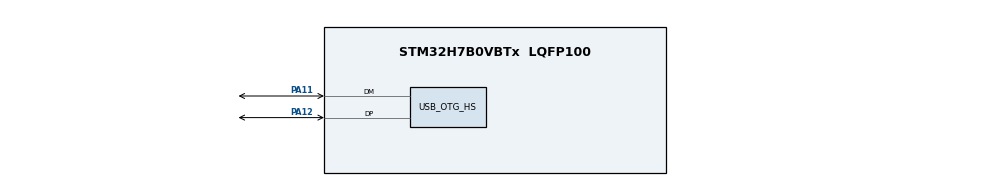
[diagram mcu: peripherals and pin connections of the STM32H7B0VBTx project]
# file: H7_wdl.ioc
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CORTEX_M7.default_mode_Activation=1
Mcu.Family=STM32H7
Mcu.Name=STM32H7B0VBTx
Mcu.Package=LQFP100
NVIC.OTG_HS_IRQn=true\:0\:0\:false\:false\:true\:false\:true\:true
NVIC.PriorityGroup=NVIC_PRIORITYGROUP_4
PA11.Mode=Device_Only_FS
PA11.Signal=USB_OTG_HS_DM
PA12.Mode=Device_Only_FS
PA12.Signal=USB_OTG_HS_DP
PH0-OSC_IN.Mode=HSE-External-Oscillator
PH0-OSC_IN.Signal=RCC_OSC_IN
PH1-OSC_OUT.Mode=HSE-External-Oscillator
PH1-OSC_OUT.Signal=RCC_OSC_OUT
ProjectManager.HeapSize=0x10000
ProjectManager.StackSize=0x10000
ProjectManager.TargetToolchain=STM32CubeIDE
RCC.ADCFreq_Value=280000000
RCC.APB1Freq_Value=140000000
RCC.APB2Freq_Value=140000000
RCC.APB3Freq_Value=140000000
RCC.APB4Freq_Value=140000000
RCC.CDPPRE=RCC_APB3_DIV2
RCC.CDPPRE1=RCC_APB1_DIV2
RCC.CDPPRE2=RCC_APB2_DIV2
RCC.CortexFreq_Value=280000000
RCC.DIVM1=5
RCC.DIVM2=5
RCC.DIVM3=5
RCC.DIVN1=112
RCC.DIVN2=112
RCC.DIVN3=112
RCC.HCLKFreq_Value=280000000
RCC.HSE_VALUE=25000000
RCC.PLL2FRACN=0
RCC.PLL3FRACN=0
RCC.PLLFRACN=0
RCC.PLLSourceVirtual=RCC_PLLSOURCE_HSE
RCC.SRDPPRE=RCC_APB4_DIV2
RCC.SYSCLKFreq_VALUE=280000000
RCC.SYSCLKSource=RCC_SYSCLKSOURCE_PLLCLK
RCC.USBCLockSelection=RCC_USBCLKSOURCE_HSI48
RCC.USBFreq_Value=48000000
USB_DEVICE.CLASS_NAME_HS=CDC
USB_DEVICE.USBD_LPM_ENABLED=0
USB_DEVICE.USBD_MAX_STR_DESC_SIZ=512
USB_DEVICE.VirtualMode=Cdc
USB_DEVICE.VirtualModeHS=Cdc_HS
USB_OTG_HS.VirtualMode-Device_Only_FS=Device_Only_FS
VP_USB_DEVICE_VS_USB_DEVICE_CDC_HS.Mode=CDC_HS
board=custom

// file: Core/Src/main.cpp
#include "usb_device.h"
#include "main.h"

#include "string.h"
#include <H7ADC.h>
//#include "H7UART.h"
#include "OW25Qxx.h"
#include "H7Power.h"
#include "Week.h"
#include "Screen.h"
#include "ff.h"
#include "Anjian.h"
#include "math.h"
#include "Set.h"

#pragma GCC diagnostic push
#pragma GCC diagnostic ignored "-Wunused-parameter"
#pragma GCC diagnostic ignored "-Wmissing-declarations"
#pragma GCC diagnostic ignored "-Wreturn-type"

kiss_fft_cpx 	*cx_in;//[nFFT];
kiss_fft_cpx 	cx_out[nFFT];//FFT后，把cx_in中的加速度数据搬到后半部分来
kiss_fft_cpx 	st_tmp[nFFT+34];//fft后，后半部分包含幅值（平方和再开方）
uint16_t 		adcData[nFFT]		__attribute__((section(".RAM_CD")));;//ADC数据缓冲区
float *fftJieguo;
float *fftJieguoTMP;
float *shiyuShuju;
uint16_t 		bufLCD[240*135] 		__attribute__((section(".DTCMRAM1")));//液晶数据缓冲区
u8*				_bmp;//[nFFT]		 	__attribute__((section(".DTCMRAM2")));//读取图像文件的临时缓冲区
char 			nameItem[32][20] 		__attribute__((section(".DTCMRAM2")));
char 			zhushiItem[32][128] 	__attribute__((section(".DTCMRAM2")));
char 			canshuTxt[4096]		__attribute__((section(".DTCMRAM2")));
u8 				work[4096] 				__attribute__((section(".DTCMRAM2")));
u8 				bCeDianchi=1;
u8 				bGaiTime=0;
u32				kaijiTime=0;
u8					bUSB=0;
u8					bMapped=0;
int main(void)
{

	__HAL_RCC_GPIOH_CLK_ENABLE();
	__HAL_RCC_GPIOA_CLK_ENABLE();
	__HAL_RCC_GPIOB_CLK_ENABLE();
	__HAL_RCC_GPIOC_CLK_ENABLE();
	__HAL_RCC_GPIOD_CLK_ENABLE();
	__HAL_RCC_GPIOE_CLK_ENABLE();

	MPU_Config();
	SCB_EnableDCache();
	SCB_EnableICache();
	HAL_Init();//初始化定时器
	SystemClock_Config();//配置时钟并重新初始化定时器
	HAL_Delay(200);

	fftJieguo=(float *)&st_tmp[nFFT/2];
	shiyuShuju=(float *)&cx_out[nFFT/2];
	fftJieguoTMP=(float *)&st_tmp;
	_bmp=(u8 *)&st_tmp;
	cx_in=(kiss_fft_cpx *)(0x90000000+0x800000-nFFT*8);

	Set m_set;
	m_set.init();

	H7Power m_power;
	m_power.init();

	OW25Qxx m_o25;
	m_o25.init();
	FATFS fs[1];
	f_mount(&fs[0], "0:", 0); //加载驱动器

	Screen m_screen(fs);
	m_screen.init();
	m_screen.LOGO();
	MX_USB_DEVICE_Init();
	HAL_Delay(2500);
	Set::setUSBinput();

	Anjian::init();
	H7ADC m_ad;
	m_ad.init();
	m_ad.setCedianchi(true,10000);
 	u32 ms=0;
 	bool b;
	while (1)
	{
		m_ad.run();
		if(uwTick!=ms)//uwTick
		{
			b=Anjian::run();
			ms=uwTick;
			m_screen.run(ms,b);
			m_power.run(ms);//主要功能是判断是否修改了config文件，以便时钟校准
			if(ms%100==0)
				m_power.getRTCtime();
		}
	}

}

void SystemClock_Config(void)
{
	RCC_OscInitTypeDef RCC_OscInitStruct;
	memset(&RCC_OscInitStruct,0,sizeof(RCC_OscInitStruct));

	RCC_ClkInitTypeDef RCC_ClkInitStruct ;
	memset(&RCC_ClkInitStruct,0,sizeof(RCC_ClkInitStruct));

	/** Supply configuration update enable
	 */
	HAL_PWREx_ConfigSupply(PWR_LDO_SUPPLY);

	/** Configure the main internal regulator output voltage
	 */
	__HAL_PWR_VOLTAGESCALING_CONFIG(PWR_REGULATOR_VOLTAGE_SCALE0);

	while(!__HAL_PWR_GET_FLAG(PWR_FLAG_VOSRDY)) {}

	/*AXI clock gating */
	RCC->CKGAENR = 0xFFFFFFFF;

	RCC_OscInitStruct.OscillatorType = RCC_OSCILLATORTYPE_HSI48|RCC_OSCILLATORTYPE_HSE|RCC_OSCILLATORTYPE_LSE;
	RCC_OscInitStruct.HSEState = RCC_HSE_ON;
	RCC_OscInitStruct.LSEState = RCC_LSE_ON;
	RCC_OscInitStruct.HSI48State = RCC_HSI48_ON;
	RCC_OscInitStruct.PLL.PLLState = RCC_PLL_ON;
	RCC_OscInitStruct.PLL.PLLSource = RCC_PLLSOURCE_HSE;
	RCC_OscInitStruct.PLL.PLLM = 5;
	RCC_OscInitStruct.PLL.PLLN = 56;
	RCC_OscInitStruct.PLL.PLLP = 2;
	RCC_OscInitStruct.PLL.PLLQ = 2;
	RCC_OscInitStruct.PLL.PLLR = 2;
	RCC_OscInitStruct.PLL.PLLRGE = RCC_PLL1VCIRANGE_2;
	RCC_OscInitStruct.PLL.PLLVCOSEL = RCC_PLL1VCOWIDE;
	RCC_OscInitStruct.PLL.PLLFRACN = 0;
	if (HAL_RCC_OscConfig(&RCC_OscInitStruct) != HAL_OK)
	{
		Error_Handler();
	}

	/** Initializes the CPU, AHB and APB buses clocks
	 */
	RCC_ClkInitStruct.ClockType = RCC_CLOCKTYPE_HCLK|RCC_CLOCKTYPE_SYSCLK
			|RCC_CLOCKTYPE_PCLK1|RCC_CLOCKTYPE_PCLK2
			|RCC_CLOCKTYPE_D3PCLK1|RCC_CLOCKTYPE_D1PCLK1;
	RCC_ClkInitStruct.SYSCLKSource = RCC_SYSCLKSOURCE_PLLCLK;
	RCC_ClkInitStruct.SYSCLKDivider = RCC_SYSCLK_DIV1;
	RCC_ClkInitStruct.AHBCLKDivider = RCC_HCLK_DIV1;
	RCC_ClkInitStruct.APB3CLKDivider = RCC_APB3_DIV2;
	RCC_ClkInitStruct.APB1CLKDivider = RCC_APB1_DIV2;
	RCC_ClkInitStruct.APB2CLKDivider = RCC_APB2_DIV2;
	RCC_ClkInitStruct.APB4CLKDivider = RCC_APB4_DIV2;

	if (HAL_RCC_ClockConfig(&RCC_ClkInitStruct, FLASH_LATENCY_6) != HAL_OK)
	{
		Error_Handler();
	}
}

/* MPU Configuration */

void MPU_Config(void)
{
	MPU_Region_InitTypeDef MPU_InitStruct ;
	memset(&MPU_InitStruct,0,sizeof(MPU_InitStruct));

	/* Disables the MPU */
	HAL_MPU_Disable();

	/** Initializes and configures the Region and the memory to be protected

	MPU_InitStruct.Enable = MPU_REGION_ENABLE;
	MPU_InitStruct.Number = MPU_REGION_NUMBER0;
	MPU_InitStruct.BaseAddress = 0x0;
	MPU_InitStruct.Size = MPU_REGION_SIZE_4GB;
	MPU_InitStruct.SubRegionDisable = 0x87;
	MPU_InitStruct.TypeExtField = MPU_TEX_LEVEL0;
	MPU_InitStruct.AccessPermission = MPU_REGION_NO_ACCESS;
	MPU_InitStruct.DisableExec = MPU_INSTRUCTION_ACCESS_DISABLE;
	MPU_InitStruct.IsShareable = MPU_ACCESS_SHAREABLE;
	MPU_InitStruct.IsCacheable = MPU_ACCESS_NOT_CACHEABLE;
	MPU_InitStruct.IsBufferable = MPU_ACCESS_NOT_BUFFERABLE;

	HAL_MPU_ConfigRegion(&MPU_InitStruct);*/

	/* 配置AXI SRAM的MPU属性为Write back, Read allocate，Write allocate */
	MPU_InitStruct.Enable           = MPU_REGION_ENABLE;
	MPU_InitStruct.BaseAddress      = 0x24000000;
	MPU_InitStruct.Size             = MPU_REGION_SIZE_1MB;
	MPU_InitStruct.SubRegionDisable = 0x00;
	//	MPU_InitStruct.BaseAddress = 0x0;
	//	MPU_InitStruct.Size = MPU_REGION_SIZE_4GB;
	//	MPU_InitStruct.SubRegionDisable = 0x87;

	MPU_InitStruct.AccessPermission = MPU_REGION_FULL_ACCESS;
	MPU_InitStruct.Number           = MPU_REGION_NUMBER0;
	MPU_InitStruct.TypeExtField     = MPU_TEX_LEVEL1;
	MPU_InitStruct.IsBufferable     = MPU_ACCESS_BUFFERABLE;
	MPU_InitStruct.IsCacheable      = MPU_ACCESS_CACHEABLE;
	MPU_InitStruct.IsShareable      = MPU_ACCESS_NOT_SHAREABLE;
	//	MPU_InitStruct.IsShareable = MPU_ACCESS_SHAREABLE;
	//	MPU_InitStruct.IsCacheable = MPU_ACCESS_NOT_CACHEABLE;
	//	MPU_InitStruct.IsBufferable = MPU_ACCESS_NOT_BUFFERABLE;

	HAL_MPU_ConfigRegion(&MPU_InitStruct);

	HAL_MPU_Enable(MPU_PRIVILEGED_DEFAULT);

}
void Error_Handler(void)
{
	NVIC_SystemReset();
#if 0
	__disable_irq();
	while (1)
	{
	}
#endif
}
